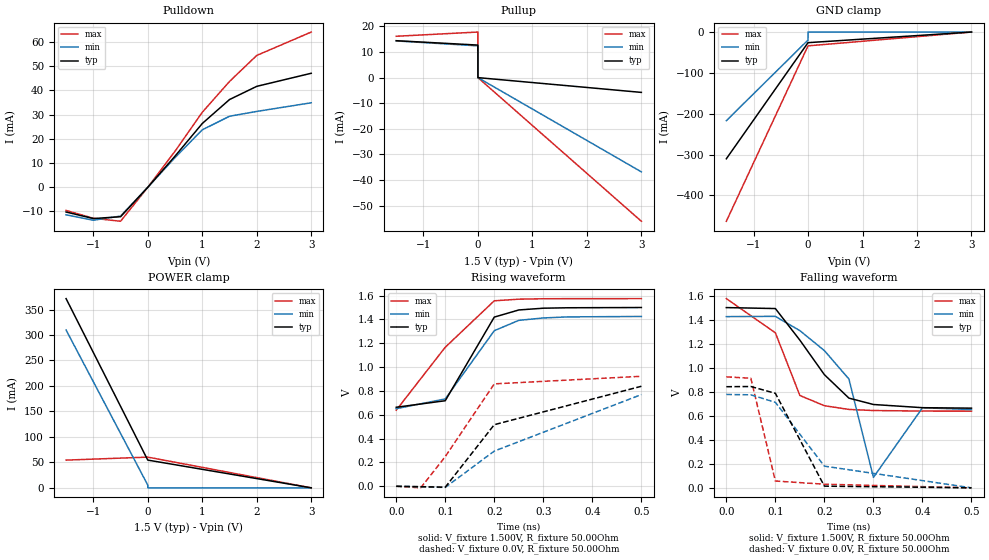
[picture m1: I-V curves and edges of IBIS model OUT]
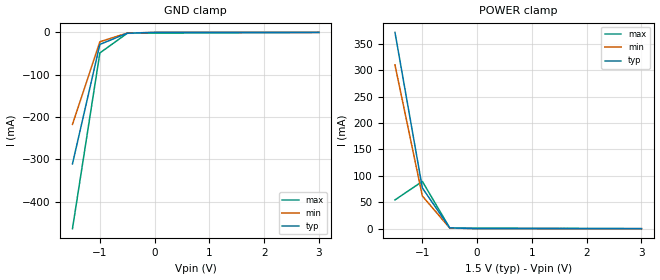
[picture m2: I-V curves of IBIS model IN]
[IBIS Ver]   4.2
[File Name]   c_comp_extended.ibs
[Date]   13/07/2026
[File Rev]   1.0
[Source]   Structure taken from commercial model but values and details changed and unused models removed.
[Notes]   This file contains models which have c_comp_pu/pd/gnd/pwr values implemented as well as
|   a submodel to be used for testing purposes.
| COMPONENT: InAndOut
[Component]   InAndOut
[Manufacturer]   Bin Chicken Inc.
[Package Model]   InAndOut
[Package]
|   typ   min   max
R_pkg   280m   200m   360m
L_pkg   1.8nH   1.2nH   2.5nH
C_pkg   0.3pF   0.2pF   0.5pF
[Pin]   signal_name model_name   R_pin   L_pin   C_pin
1   OUT   OUT   28m   1.6nH   0.4pF
2   IN   IN   32m   1.7nH   0.4pF
3   VSS   GND
4   VDD   POWER
|   Model Selector
[Model Selector] InAndOut
OUT   I/O Model
IN   Input Model
| Models and submodels in the file (2): OUT (I/O), IN (Input)
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| MODEL OUT I/O Model
[Model]   OUT
Model_type   I/O
Vinl = 600.0mV
Vinh = 900.0mV
Vmeas = 80.0mV
Vref = 80.0mV
Cref = 0.0pF
Rref = 2.0Ohm
|   typ   min   max
C_comp_pullup   0.6520pF   0.6pF   0.688pF
C_comp_pulldown   0.6500pF   0.62pF   0.69pF
[Model Spec]
| Input threshold voltage corners
Vinl   0.60V   0.562V   0.638V
Vinh   0.90V   0.862V   0.938V
| Measurement voltage corners
Vmeas   0.800V   0.712V   0.788V
| Timing spec test load voltage corners
Vref   0.800V   0.712V   0.788V
Vcross_low   = 0.600V
Vcross_high  = 0.900V
Vdiff_ac   = 300mV
Vdiff_dc   = 200mV
Tdiffslew_ac = 10.0ns
[Voltage Range]   1.50V   1.420V   1.580V
[Pullup Reference]   1.50V   1.420V   1.580V
[Temperature Range]   50.0   110.0   -4.0
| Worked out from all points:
|   slope of the pulldown table from 0 to 0.225 V, typ, clamps not added: 38.9 ohm
|   slope of the pullup table from 0 to 0.225 V, typ, clamps not added: 519 ohm
|   falling waveform, V_fixture 1.500V, R_fixture 50.00Ohm: 20-80 % time 98.2ps typ, 94.7ps min, 78.7ps max; typ from 1.5 V to 0.663 V
|   rising waveform, V_fixture 1.500V, R_fixture 50.00Ohm: 20-80 % time 71.6ps typ, 81.1ps min, 121ps max; typ from 0.663 V to 1.5 V
|   rising waveform, V_fixture 0.0V, R_fixture 50.00Ohm: 20-80 % time 210ps typ, 249ps min, 92.5ps max; typ from 0 V to 0.839 V
|   falling waveform, V_fixture 0.0V, R_fixture 50.00Ohm: 20-80 % time 65.4ps typ, 125ps min, 32.4ps max; typ from 0.841 V to 0 V
[Pulldown]
|   Voltage   I(typ)   I(min)   I(max)
-1.5V     -10.21mA   -11.36mA   -9.561mA
-1V       -12.91mA   -13.61mA   -12.8mA
-500mV    -12.16mA   -11.89mA   -14.04mA
0V        -2.491uA   -3.371uA   -6.135uA
500mV     12.86mA    12.25mA    14.88mA
1V        26.33mA    23.71mA    30.96mA
1.5V      36.21mA    29.31mA    43.68mA
2V        41.66mA    31.31mA    54.43mA
3V        47.06mA    34.87mA    64.07mA
[GND Clamp]
|   Voltage   I(typ)   I(min)   I(max)
-1.5V     -310.3mA   -217mA     -463.3mA
-1mV      -26mA      -19.6mA    -33.86mA
0V        NA         0A         NA
3V        0A         0A         0A
[Pullup]
|   Voltage   I(typ)   I(min)   I(max)
-1.5V     14.44mA    14.35mA    16.17mA
-1mV      12.73mA    12.43mA    17.83mA
0V        5.626uA    4.124uA    16.69uA
3V        -5.772mA   -36.85mA   -56.16mA
[POWER Clamp]
|   Voltage   I(typ)   I(min)   I(max)
-1.5V     371.5mA    309.9mA    54.41mA
-1mV      54.49mA    5.485mA    60.29mA
0V        NA         0A         NA
3V        0A         0A         0A
[Ramp]
R_load = 50.00Ohm
|   typ   min   max
dV/dt_r   500mV/80ps  50mV/100ps 550mV/60ps
dV/dt_f   500mV/80ps  50mV/110ps 560mV/60ps
[Falling Waveform]
V_fixture = 1.500V
V_fixture_min = 1.42V
V_fixture_max = 1.58V
R_fixture = 50.00Ohm
|   Time   V(typ)   V(min)   V(max)
0s        1.5V       1.425V     1.575V
100ps     1.492V     1.427V     1.29V
150ps     1.229V     1.308V     768.4mV
200ps     941.6mV    1.142V     683.5mV
250ps     746.5mV    905.5mV    652.4mV
300ps     693.6mV    87.18mV    643.4mV
400ps     666.9mV    666.2mV    638.8mV
450ps     665mV      659.3mV    638.5mV
500ps     663.1mV    651.2mV    638.2mV
[Rising Waveform]
V_fixture = 1.500V
V_fixture_min = 1.42V
V_fixture_max = 1.58V
R_fixture = 50.00Ohm
|   Time   V(typ)   V(min)   V(max)
0s        663.1mV    651.2mV    638.2mV
100ps     717.7mV    733.1mV    1.167V
200ps     1.419V     1.305V     1.556V
250ps     1.479V     1.392V     1.57V
300ps     1.494V     1.412V     1.573V
350ps     1.498V     1.421V     1.574V
500ps     1.5V       1.425V     1.575V
[Rising Waveform]
V_fixture = 0.0V
V_fixture_min = 0.0V
V_fixture_max = 0.0V
R_fixture = 50.00Ohm
|   Time   V(typ)   V(min)   V(max)
0s        26.08uV    44.49uV    97.36uV
50ps      -3.149mV   -4.874mV   -13.05mV
100ps     -8.065mV   -9.618mV   248.8mV
200ps     516.8mV    295.4mV    859.2mV
500ps     839.1mV    769.3mV    922.9mV
[Falling Waveform]
V_fixture = 0.0V
V_fixture_min = 0.0V
V_fixture_max = 0.0V
R_fixture = 50.00Ohm
|   Time   V(typ)   V(min)   V(max)
0s        841.5mV    777.1mV    923.5mV
50ps      843.2mV    774mV      911.8mV
100ps     786.5mV    711.7mV    56.76mV
200ps     14mV       180.5mV    30.04mV
500ps     26.08uV    44.49uV    97.36uV
| MODEL IN
[Model]   IN
Model_type   Input
Vinl = 600.0mV
Vinh = 900.0mV
|   typ   min   max
C_comp_power_clamp   0.574pF   0.52pF   0.645pF
C_comp_gnd_clamp   0.576pF   0.54pF   0.66pF
[Model Spec]
| Input threshold voltage corners
Vinl   0.60V   0.56V   0.64V
Vinh   0.90V   0.86V   0.94V
Vcross_low   = 0.600V
Vcross_high  = 0.900V
Vdiff_ac   = 300mV
Vdiff_dc   = 200mV
Tdiffslew_ac = 10.0ns
[Voltage Range]   1.50V   1.4V   1.6V
[POWER Clamp Reference]   1.50V   1.4V   1.6V
[Temperature Range]   50.0   110.0   -4.0
[Add Submodel]
| Submodel Name   Mode
ODT   Non-Driving
[GND Clamp]
|   Voltage   I(typ)   I(min)   I(max)
-1.5V     -310.3mA   -217mA     -463.3mA
-1V       -28.36mA   -22.12mA   -48.52mA
-500mV    -1.937mA   -1.596mA   -2.09mA
0V        0A         0A         NA
3V        0A         0A         0A
[POWER Clamp]
|   Voltage   I(typ)   I(min)   I(max)
-1.5V     371.5mA    309.9mA    54.41mA
-1V       77.02mA    61.82mA    89.45mA
-500mV    1.487mA    1.058mA    1.293mA
0V        0A         0A         NA
3V        0A         0A         0A
